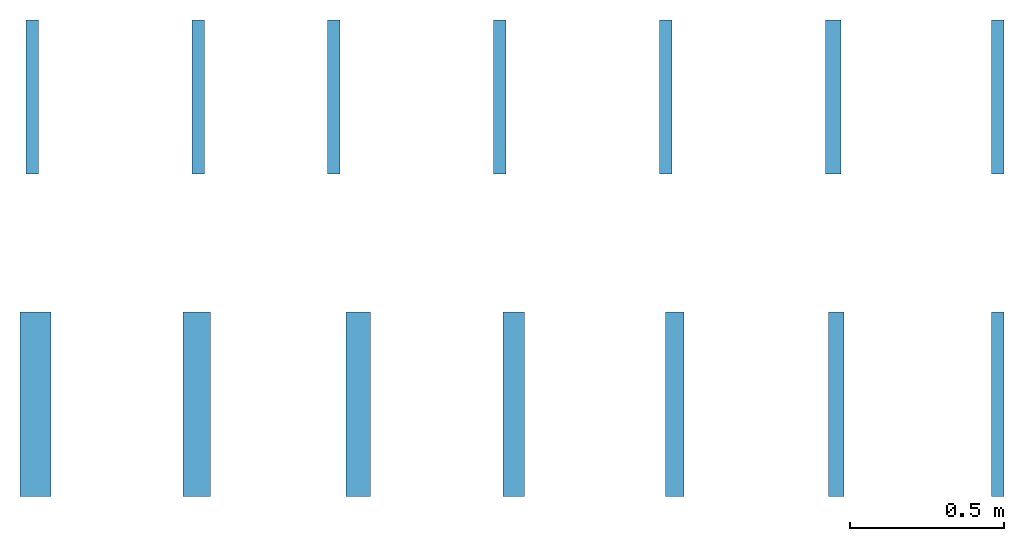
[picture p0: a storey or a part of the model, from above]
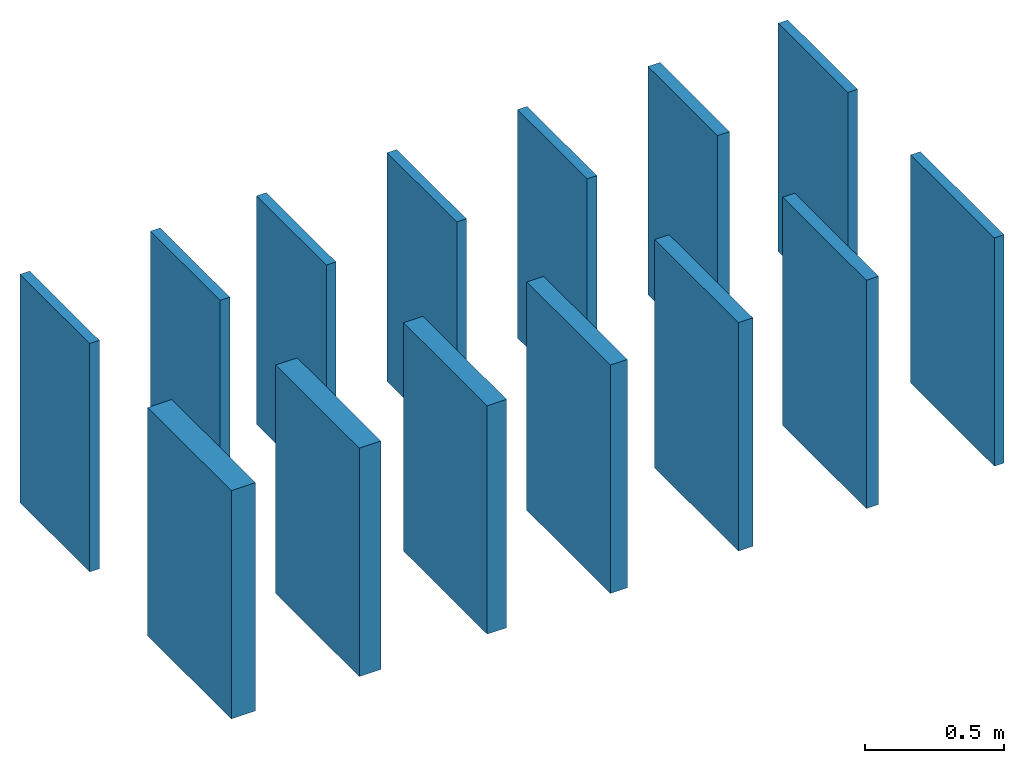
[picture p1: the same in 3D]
Properties of the parts of a building model (IFC2X3)

# File
Description: ViewDefinition [CoordinationView_V2.0]
File name: 0001
Time: 2017-06-13T12:44:01
Written by: The EXPRESS Data Manager Version 5.02.0100.07 : 28 Aug 2013
Made in: 20170223_1515(x64) - Exporter 18.0.0.420 - Alternate UI 18.0.0.420
Comment: STEP Physical File produced by: The EXPRESS Data Manager Version 5.02.0100.07 : 28 Aug 2013 * Module: EDMstepFileFactory/EDMstandAlone * Creation date: Tue Jun 13 12:44:01 2017 * Host: JAVIER * Database: C:\Users\JAVIER~1.DOM\AppData\Local\Temp\{8D6697EA-2A68-472B-9E3C-26883689C2F3}\ifc * Database version: 5507 * Database creation date: Tue Jun 13 12:44:00 2017 * Schema: IFC2X3 * Model: DataRepository.ifc * Model creation date: Tue Jun 13 12:44:01 2017 * Header model: DataRepository.ifc_HeaderModel * Header model creation date: Tue Jun 13 12:44:01 2017 * EDMuser: sdai-user * EDMgroup: sdai-group * License ID and type: 5605 : Permanent license. Expiry date: * EDMstepFileFactory options: 020000

# IfcProject, 0001
LongName: Nombre de proyecto; Phase: Estado de proyecto

# IfcSite, Default
RefLatitude: 40, 24, 0, 5493; RefLongitude: -3, -40, -59, -880065; RefElevation: 0 m

# IfcBuilding
Pset_BuildingCommon - NumberOfStoreys: 1

# IfcBuildingStorey, Nivel 1
LongName: Nivel 1; Elevation: 0 m

# IfcWallStandardCase: Muro básico:Grafipol TR-SATE_1000x500x40mm (6)
In: Nivel 1
Type - PredefinedType: STANDARD; Material: VALERO Grafipol® TR-SATE 0.04 m
Pset_WallCommon - Reference: Grafipol TR-SATE_1000x500x40mm; LoadBearing: no; ExtendToStructure: no; IsExternal: no; FireRating: E; ThermalTransmittance: 0.775 kg/K/s3
Pset_ManufacturerTypeInformation - Manufacturer: Grupo Valero - José Manuel Valero, S. L.
Name (Muro básico:Grafipol TR-SATE_1000x500x40mm:...)
169380
173285
173347
173348
173803
173804

# IfcWallStandardCase: Muro básico:Grafipol TR-SATE_1000x500x50mm, Muro básico:Grafipol TR-SATE_1000x500x50mm:173226
In: Nivel 1
Type - PredefinedType: STANDARD; Material: VALERO Grafipol® TR-SATE 0.05 m
Pset_WallCommon - LoadBearing: no; ExtendToStructure: no; IsExternal: no; Reference: Grafipol TR-SATE_1000x500x50mm; FireRating: E; ThermalTransmittance: 0.62 kg/K/s3
Pset_ManufacturerTypeInformation - Manufacturer: Grupo Valero - José Manuel Valero, S. L.

# IfcWallStandardCase: Muro básico:Grafipol TR-SATE_1000x600x100mm, Muro básico:Grafipol TR-SATE_1000x600x100mm:174087
In: Nivel 1
Type - PredefinedType: STANDARD; Material: VALERO Grafipol® TR-SATE 0.1 m
Pset_WallCommon - LoadBearing: no; ExtendToStructure: no; IsExternal: no; Reference: Grafipol TR-SATE_1000x600x100mm; FireRating: E; ThermalTransmittance: 0.31 kg/K/s3
Pset_ManufacturerTypeInformation - Manufacturer: Grupo Valero - José Manuel Valero, S. L.

# IfcWallStandardCase: Muro básico:Grafipol TR-SATE_1000x600x40mm, Muro básico:Grafipol TR-SATE_1000x600x40mm:173839
In: Nivel 1
Type - PredefinedType: STANDARD; Material: VALERO Grafipol® TR-SATE 0.04 m
Pset_WallCommon - LoadBearing: no; ExtendToStructure: no; IsExternal: no; Reference: Grafipol TR-SATE_1000x600x40mm; FireRating: E; ThermalTransmittance: 0.775 kg/K/s3
Pset_ManufacturerTypeInformation - Manufacturer: Grupo Valero - José Manuel Valero, S. L.

# IfcWallStandardCase: Muro básico:Grafipol TR-SATE_1000x600x50mm, Muro básico:Grafipol TR-SATE_1000x600x50mm:174015
In: Nivel 1
Type - PredefinedType: STANDARD; Material: VALERO Grafipol® TR-SATE 0.05 m
Pset_WallCommon - LoadBearing: no; ExtendToStructure: no; IsExternal: no; Reference: Grafipol TR-SATE_1000x600x50mm; FireRating: E; ThermalTransmittance: 0.62 kg/K/s3
Pset_ManufacturerTypeInformation - Manufacturer: Grupo Valero - José Manuel Valero, S. L.

# IfcWallStandardCase: Muro básico:Grafipol TR-SATE_1000x600x60mm, Muro básico:Grafipol TR-SATE_1000x600x60mm:174058
In: Nivel 1
Type - PredefinedType: STANDARD; Material: VALERO Grafipol® TR-SATE 0.06 m
Pset_WallCommon - LoadBearing: no; ExtendToStructure: no; IsExternal: no; Reference: Grafipol TR-SATE_1000x600x60mm; FireRating: E; ThermalTransmittance: 0.516667 kg/K/s3
Pset_ManufacturerTypeInformation - Manufacturer: Grupo Valero - José Manuel Valero, S. L.

# IfcWallStandardCase: Muro básico:Grafipol TR-SATE_1000x600x70mm, Muro básico:Grafipol TR-SATE_1000x600x70mm:174059
In: Nivel 1
Type - PredefinedType: STANDARD; Material: VALERO Grafipol® TR-SATE 0.07 m
Pset_WallCommon - LoadBearing: no; ExtendToStructure: no; IsExternal: no; Reference: Grafipol TR-SATE_1000x600x70mm; FireRating: E; ThermalTransmittance: 0.442857 kg/K/s3
Pset_ManufacturerTypeInformation - Manufacturer: Grupo Valero - José Manuel Valero, S. L.

# IfcWallStandardCase: Muro básico:Grafipol TR-SATE_1000x600x80mm, Muro básico:Grafipol TR-SATE_1000x600x80mm:174085
In: Nivel 1
Type - PredefinedType: STANDARD; Material: VALERO Grafipol® TR-SATE 0.08 m
Pset_WallCommon - LoadBearing: no; ExtendToStructure: no; IsExternal: no; Reference: Grafipol TR-SATE_1000x600x80mm; FireRating: E; ThermalTransmittance: 0.3875 kg/K/s3
Pset_ManufacturerTypeInformation - Manufacturer: Grupo Valero - José Manuel Valero, S. L.

# IfcWallStandardCase: Muro básico:Grafipol TR-SATE_1000x600x90mm, Muro básico:Grafipol TR-SATE_1000x600x90mm:174086
In: Nivel 1
Type - PredefinedType: STANDARD; Material: VALERO Grafipol® TR-SATE 0.09 m
Pset_WallCommon - LoadBearing: no; ExtendToStructure: no; IsExternal: no; Reference: Grafipol TR-SATE_1000x600x90mm; FireRating: E; ThermalTransmittance: 0.344444 kg/K/s3
Pset_ManufacturerTypeInformation - Manufacturer: Grupo Valero - José Manuel Valero, S. L.
